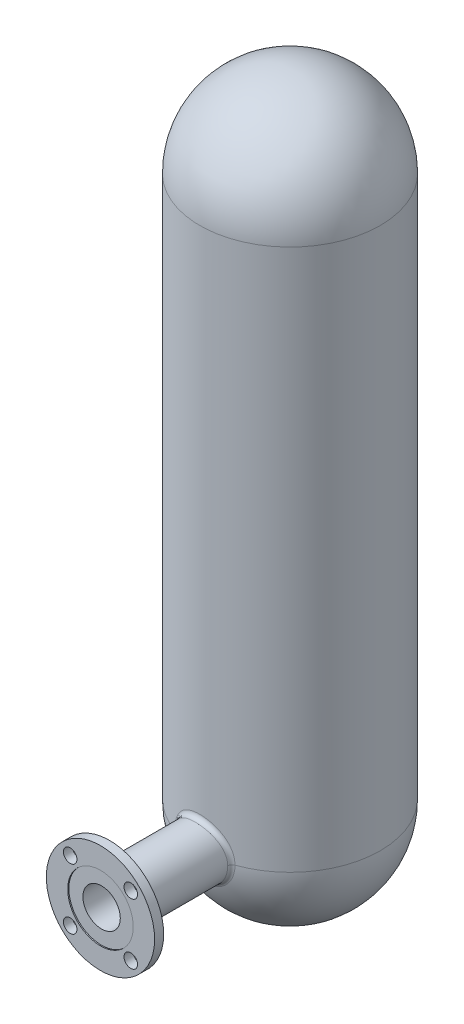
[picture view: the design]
ISO-10303-21;
HEADER;
FILE_DESCRIPTION(('STEP AP214'),'2;1');
FILE_NAME('part.step','',(''),(''),'','','');
FILE_SCHEMA(('AUTOMOTIVE_DESIGN { 1 0 10303 214 1 1 1 1 }'));
ENDSEC;
DATA;
#1=APPLICATION_CONTEXT('core data for automotive mechanical design processes');
#2=APPLICATION_PROTOCOL_DEFINITION('international standard','automotive_design',2000,#1);
#3=PRODUCT_CONTEXT('',#1,'mechanical');
#4=PRODUCT('Part','Part','',(#3));
#5=PRODUCT_RELATED_PRODUCT_CATEGORY('part','',(#4));
#6=PRODUCT_DEFINITION_FORMATION('','',#4);
#7=PRODUCT_DEFINITION_CONTEXT('part definition',#1,'design');
#8=PRODUCT_DEFINITION('design','',#6,#7);
#9=PRODUCT_DEFINITION_SHAPE('','',#8);
#10=(LENGTH_UNIT() NAMED_UNIT(*) SI_UNIT(.MILLI.,.METRE.));
#11=(NAMED_UNIT(*) PLANE_ANGLE_UNIT() SI_UNIT($,.RADIAN.));
#12=(NAMED_UNIT(*) SI_UNIT($,.STERADIAN.) SOLID_ANGLE_UNIT());
#13=UNCERTAINTY_MEASURE_WITH_UNIT(LENGTH_MEASURE(1.E-05),#10,'distance_accuracy_value','');
#14=(GEOMETRIC_REPRESENTATION_CONTEXT(3) GLOBAL_UNCERTAINTY_ASSIGNED_CONTEXT((#13)) GLOBAL_UNIT_ASSIGNED_CONTEXT((#10,
#11,#12)) REPRESENTATION_CONTEXT('',''));
#15=CARTESIAN_POINT('',(0.,0.,0.));
#16=DIRECTION('',(0.,0.,1.));
#17=DIRECTION('',(1.,0.,0.));
#18=AXIS2_PLACEMENT_3D('',#15,#16,#17);
#19=CARTESIAN_POINT('',(0.,0.,0.));
#20=DIRECTION('',(0.,0.,1.));
#21=DIRECTION('',(1.,0.,0.));
#22=AXIS2_PLACEMENT_3D('',#19,#20,#21);
#23=PLANE('',#22);
#24=CARTESIAN_POINT('',(0.,0.,0.));
#25=DIRECTION('',(0.,0.,1.));
#26=DIRECTION('',(1.,0.,0.));
#27=AXIS2_PLACEMENT_3D('',#24,#25,#26);
#28=CIRCLE('',#27,44.45);
#29=CARTESIAN_POINT('',(44.45,0.,0.));
#30=VERTEX_POINT('',#29);
#31=EDGE_CURVE('E81',#30,#30,#28,.T.);
#32=ORIENTED_EDGE('',*,*,#31,.T.);
#33=EDGE_LOOP('',(#32));
#34=FACE_BOUND('',#33,.T.);
#35=CARTESIAN_POINT('',(-42.6562165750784,42.6562165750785,0.));
#36=DIRECTION('',(0.,0.,1.));
#37=DIRECTION('',(0.,1.,0.));
#38=AXIS2_PLACEMENT_3D('',#35,#36,#37);
#39=CIRCLE('',#38,9.525);
#40=CARTESIAN_POINT('',(-42.6562165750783,52.1812165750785,0.));
#41=VERTEX_POINT('',#40);
#42=EDGE_CURVE('E136',#41,#41,#39,.T.);
#43=ORIENTED_EDGE('',*,*,#42,.T.);
#44=EDGE_LOOP('',(#43));
#45=FACE_BOUND('',#44,.T.);
#46=CARTESIAN_POINT('',(42.6562165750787,-42.6562165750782,0.));
#47=DIRECTION('',(0.,0.,1.));
#48=DIRECTION('',(0.,-1.,0.));
#49=AXIS2_PLACEMENT_3D('',#46,#47,#48);
#50=CIRCLE('',#49,9.525);
#51=CARTESIAN_POINT('',(42.6562165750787,-52.1812165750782,0.));
#52=VERTEX_POINT('',#51);
#53=EDGE_CURVE('E148',#52,#52,#50,.T.);
#54=ORIENTED_EDGE('',*,*,#53,.T.);
#55=EDGE_LOOP('',(#54));
#56=FACE_BOUND('',#55,.T.);
#57=CARTESIAN_POINT('',(0.,0.,0.));
#58=DIRECTION('',(0.,0.,1.));
#59=DIRECTION('',(1.,0.,0.));
#60=AXIS2_PLACEMENT_3D('',#57,#58,#59);
#61=CIRCLE('',#60,76.2);
#62=CARTESIAN_POINT('',(76.2,0.,0.));
#63=VERTEX_POINT('',#62);
#64=EDGE_CURVE('E155',#63,#63,#61,.T.);
#65=ORIENTED_EDGE('',*,*,#64,.F.);
#66=EDGE_LOOP('',(#65));
#67=FACE_BOUND('',#66,.T.);
#68=CARTESIAN_POINT('',(42.6562165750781,42.6562165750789,0.));
#69=DIRECTION('',(0.,0.,1.));
#70=DIRECTION('',(1.,0.,0.));
#71=AXIS2_PLACEMENT_3D('',#68,#69,#70);
#72=CIRCLE('',#71,9.525);
#73=CARTESIAN_POINT('',(52.1812165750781,42.6562165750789,0.));
#74=VERTEX_POINT('',#73);
#75=EDGE_CURVE('E151',#74,#74,#72,.T.);
#76=ORIENTED_EDGE('',*,*,#75,.T.);
#77=EDGE_LOOP('',(#76));
#78=FACE_BOUND('',#77,.T.);
#79=CARTESIAN_POINT('',(-42.6562165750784,-42.6562165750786,0.));
#80=DIRECTION('',(0.,0.,1.));
#81=DIRECTION('',(-1.,0.,0.));
#82=AXIS2_PLACEMENT_3D('',#79,#80,#81);
#83=CIRCLE('',#82,9.525);
#84=CARTESIAN_POINT('',(-52.1812165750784,-42.6562165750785,0.));
#85=VERTEX_POINT('',#84);
#86=EDGE_CURVE('E142',#85,#85,#83,.T.);
#87=ORIENTED_EDGE('',*,*,#86,.T.);
#88=EDGE_LOOP('',(#87));
#89=FACE_BOUND('',#88,.T.);
#90=ADVANCED_FACE('F34',(#34,#45,#56,#67,#78,#89),#23,.F.);
#91=CARTESIAN_POINT('',(0.,0.,12.7));
#92=DIRECTION('',(0.,0.,1.));
#93=DIRECTION('',(1.,0.,0.));
#94=AXIS2_PLACEMENT_3D('',#91,#92,#93);
#95=PLANE('',#94);
#96=CARTESIAN_POINT('',(0.,0.,12.7000000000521));
#97=DIRECTION('',(0.,0.,1.));
#98=DIRECTION('',(1.,0.,0.));
#99=AXIS2_PLACEMENT_3D('',#96,#97,#98);
#100=CIRCLE('',#99,46.101);
#101=CARTESIAN_POINT('',(46.101,0.,12.7000000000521));
#102=VERTEX_POINT('',#101);
#103=EDGE_CURVE('E346',#102,#102,#100,.T.);
#104=ORIENTED_EDGE('',*,*,#103,.F.);
#105=EDGE_LOOP('',(#104));
#106=FACE_BOUND('',#105,.T.);
#107=CARTESIAN_POINT('',(-42.6562165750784,-42.6562165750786,12.7));
#108=DIRECTION('',(0.,0.,1.));
#109=DIRECTION('',(-1.,0.,0.));
#110=AXIS2_PLACEMENT_3D('',#107,#108,#109);
#111=CIRCLE('',#110,9.525);
#112=CARTESIAN_POINT('',(-52.1812165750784,-42.6562165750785,12.7));
#113=VERTEX_POINT('',#112);
#114=EDGE_CURVE('E139',#113,#113,#111,.T.);
#115=ORIENTED_EDGE('',*,*,#114,.F.);
#116=EDGE_LOOP('',(#115));
#117=FACE_BOUND('',#116,.T.);
#118=CARTESIAN_POINT('',(42.6562165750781,42.6562165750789,12.7));
#119=DIRECTION('',(0.,0.,1.));
#120=DIRECTION('',(1.,0.,0.));
#121=AXIS2_PLACEMENT_3D('',#118,#119,#120);
#122=CIRCLE('',#121,9.525);
#123=CARTESIAN_POINT('',(52.1812165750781,42.6562165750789,12.7));
#124=VERTEX_POINT('',#123);
#125=EDGE_CURVE('E152',#124,#124,#122,.T.);
#126=ORIENTED_EDGE('',*,*,#125,.F.);
#127=EDGE_LOOP('',(#126));
#128=FACE_BOUND('',#127,.T.);
#129=CARTESIAN_POINT('',(0.,0.,12.7));
#130=DIRECTION('',(0.,0.,1.));
#131=DIRECTION('',(1.,0.,0.));
#132=AXIS2_PLACEMENT_3D('',#129,#130,#131);
#133=CIRCLE('',#132,76.2);
#134=CARTESIAN_POINT('',(76.2,0.,12.7));
#135=VERTEX_POINT('',#134);
#136=EDGE_CURVE('E75',#135,#135,#133,.T.);
#137=ORIENTED_EDGE('',*,*,#136,.T.);
#138=EDGE_LOOP('',(#137));
#139=FACE_BOUND('',#138,.T.);
#140=CARTESIAN_POINT('',(42.6562165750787,-42.6562165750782,12.7));
#141=DIRECTION('',(0.,0.,1.));
#142=DIRECTION('',(0.,-1.,0.));
#143=AXIS2_PLACEMENT_3D('',#140,#141,#142);
#144=CIRCLE('',#143,9.525);
#145=CARTESIAN_POINT('',(42.6562165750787,-52.1812165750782,12.7));
#146=VERTEX_POINT('',#145);
#147=EDGE_CURVE('E145',#146,#146,#144,.T.);
#148=ORIENTED_EDGE('',*,*,#147,.F.);
#149=EDGE_LOOP('',(#148));
#150=FACE_BOUND('',#149,.T.);
#151=CARTESIAN_POINT('',(-42.6562165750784,42.6562165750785,12.7));
#152=DIRECTION('',(0.,0.,1.));
#153=DIRECTION('',(0.,1.,0.));
#154=AXIS2_PLACEMENT_3D('',#151,#152,#153);
#155=CIRCLE('',#154,9.525);
#156=CARTESIAN_POINT('',(-42.6562165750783,52.1812165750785,12.7));
#157=VERTEX_POINT('',#156);
#158=EDGE_CURVE('E129',#157,#157,#155,.T.);
#159=ORIENTED_EDGE('',*,*,#158,.F.);
#160=EDGE_LOOP('',(#159));
#161=FACE_BOUND('',#160,.T.);
#162=ADVANCED_FACE('F166',(#106,#117,#128,#139,#150,#161),#95,.T.);
#163=CARTESIAN_POINT('',(0.,0.,12.7));
#164=DIRECTION('',(0.,0.,-1.));
#165=DIRECTION('',(-1.,0.,0.));
#166=AXIS2_PLACEMENT_3D('',#163,#164,#165);
#167=CYLINDRICAL_SURFACE('',#166,76.2);
#168=ORIENTED_EDGE('',*,*,#136,.F.);
#169=EDGE_LOOP('',(#168));
#170=FACE_BOUND('',#169,.T.);
#171=ORIENTED_EDGE('',*,*,#64,.T.);
#172=EDGE_LOOP('',(#171));
#173=FACE_BOUND('',#172,.T.);
#174=ADVANCED_FACE('F162',(#170,#173),#167,.T.);
#175=CARTESIAN_POINT('',(42.6562165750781,42.6562165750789,12.7));
#176=DIRECTION('',(0.,0.,-1.));
#177=DIRECTION('',(-1.,0.,0.));
#178=AXIS2_PLACEMENT_3D('',#175,#176,#177);
#179=CYLINDRICAL_SURFACE('',#178,9.525);
#180=ORIENTED_EDGE('',*,*,#125,.T.);
#181=EDGE_LOOP('',(#180));
#182=FACE_BOUND('',#181,.T.);
#183=ORIENTED_EDGE('',*,*,#75,.F.);
#184=EDGE_LOOP('',(#183));
#185=FACE_BOUND('',#184,.T.);
#186=ADVANCED_FACE('F184',(#182,#185),#179,.F.);
#187=CARTESIAN_POINT('',(42.6562165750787,-42.6562165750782,12.7));
#188=DIRECTION('',(0.,0.,-1.));
#189=DIRECTION('',(0.,1.,0.));
#190=AXIS2_PLACEMENT_3D('',#187,#188,#189);
#191=CYLINDRICAL_SURFACE('',#190,9.525);
#192=ORIENTED_EDGE('',*,*,#147,.T.);
#193=EDGE_LOOP('',(#192));
#194=FACE_BOUND('',#193,.T.);
#195=ORIENTED_EDGE('',*,*,#53,.F.);
#196=EDGE_LOOP('',(#195));
#197=FACE_BOUND('',#196,.T.);
#198=ADVANCED_FACE('F176',(#194,#197),#191,.F.);
#199=CARTESIAN_POINT('',(-42.6562165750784,-42.6562165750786,12.7));
#200=DIRECTION('',(0.,0.,-1.));
#201=DIRECTION('',(1.,0.,0.));
#202=AXIS2_PLACEMENT_3D('',#199,#200,#201);
#203=CYLINDRICAL_SURFACE('',#202,9.525);
#204=ORIENTED_EDGE('',*,*,#114,.T.);
#205=EDGE_LOOP('',(#204));
#206=FACE_BOUND('',#205,.T.);
#207=ORIENTED_EDGE('',*,*,#86,.F.);
#208=EDGE_LOOP('',(#207));
#209=FACE_BOUND('',#208,.T.);
#210=ADVANCED_FACE('F173',(#206,#209),#203,.F.);
#211=CARTESIAN_POINT('',(-42.6562165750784,42.6562165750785,12.7));
#212=DIRECTION('',(0.,0.,-1.));
#213=DIRECTION('',(0.,-1.,0.));
#214=AXIS2_PLACEMENT_3D('',#211,#212,#213);
#215=CYLINDRICAL_SURFACE('',#214,9.525);
#216=ORIENTED_EDGE('',*,*,#158,.T.);
#217=EDGE_LOOP('',(#216));
#218=FACE_BOUND('',#217,.T.);
#219=ORIENTED_EDGE('',*,*,#42,.F.);
#220=EDGE_LOOP('',(#219));
#221=FACE_BOUND('',#220,.T.);
#222=ADVANCED_FACE('F175',(#218,#221),#215,.F.);
#223=CARTESIAN_POINT('',(0.,0.,-254.));
#224=DIRECTION('',(0.,0.,1.));
#225=DIRECTION('',(1.,0.,0.));
#226=AXIS2_PLACEMENT_3D('',#223,#224,#225);
#227=CYLINDRICAL_SURFACE('',#226,38.1);
#228=CARTESIAN_POINT('',(0.,0.,-6.34999999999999));
#229=DIRECTION('',(0.,0.,1.));
#230=DIRECTION('',(1.,0.,0.));
#231=AXIS2_PLACEMENT_3D('',#228,#229,#230);
#232=CIRCLE('',#231,38.1);
#233=CARTESIAN_POINT('',(38.1,0.,-6.34999999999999));
#234=VERTEX_POINT('',#233);
#235=EDGE_CURVE('E78',#234,#234,#232,.F.);
#236=ORIENTED_EDGE('',*,*,#235,.T.);
#237=EDGE_LOOP('',(#236));
#238=FACE_BOUND('',#237,.T.);
#239=CARTESIAN_POINT('',(36.0912363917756,-12.2078931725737,-127.472255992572));
#240=CARTESIAN_POINT('',(35.9327782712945,-12.6763564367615,-132.110143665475));
#241=CARTESIAN_POINT('',(40.1013737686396,-14.2425420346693,-133.497386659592));
#242=CARTESIAN_POINT('',(36.2566669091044,-11.7188156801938,-127.536488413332));
#243=CARTESIAN_POINT('',(36.1103315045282,-12.1723584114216,-132.162177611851));
#244=CARTESIAN_POINT('',(40.2851854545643,-13.6719516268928,-133.558560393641));
#245=CARTESIAN_POINT('',(36.4122340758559,-11.2261412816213,-127.597372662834));
#246=CARTESIAN_POINT('',(36.2776912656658,-11.6634311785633,-132.211645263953));
#247=CARTESIAN_POINT('',(40.4580378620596,-13.0971648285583,-133.616545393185));
#248=CARTESIAN_POINT('',(36.7033555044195,-10.2343004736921,-127.712025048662));
#249=CARTESIAN_POINT('',(36.5910783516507,-10.637885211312,-132.304902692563));
#250=CARTESIAN_POINT('',(40.7815061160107,-11.9400172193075,-133.725738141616));
#251=CARTESIAN_POINT('',(36.838909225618,-9.73513388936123,-127.765792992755));
#252=CARTESIAN_POINT('',(36.7371824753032,-10.1211577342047,-132.348714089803));
#253=CARTESIAN_POINT('',(40.9321213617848,-11.3576562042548,-133.776945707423));
#254=CARTESIAN_POINT('',(37.2150749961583,-8.22912180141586,-127.915774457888));
#255=CARTESIAN_POINT('',(37.142471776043,-8.56214817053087,-132.470927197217));
#256=CARTESIAN_POINT('',(41.3500833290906,-9.60064210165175,-133.919785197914));
#257=CARTESIAN_POINT('',(37.4252357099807,-7.21363378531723,-128.000682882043));
#258=CARTESIAN_POINT('',(37.3697428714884,-7.50766486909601,-132.540437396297));
#259=CARTESIAN_POINT('',(41.583595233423,-8.41590608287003,-134.000650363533));
#260=CARTESIAN_POINT('',(37.7619395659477,-5.1689618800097,-128.137495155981));
#261=CARTESIAN_POINT('',(37.7337564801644,-5.38291751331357,-132.652459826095));
#262=CARTESIAN_POINT('',(41.9577106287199,-6.03045552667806,-134.130947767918));
#263=CARTESIAN_POINT('',(37.8886076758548,-4.13980082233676,-128.189448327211));
#264=CARTESIAN_POINT('',(37.8710238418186,-4.31159426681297,-132.695130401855));
#265=CARTESIAN_POINT('',(42.0984529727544,-4.82976762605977,-134.180426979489));
#266=CARTESIAN_POINT('',(38.0576344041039,-2.07375805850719,-128.258906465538));
#267=CARTESIAN_POINT('',(38.0540409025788,-2.16076039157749,-132.752139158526));
#268=CARTESIAN_POINT('',(42.286260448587,-2.41938440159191,-134.246577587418));
#269=CARTESIAN_POINT('',(38.0999992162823,-1.03687692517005,-128.276413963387));
#270=CARTESIAN_POINT('',(38.0999991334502,-1.08007747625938,-132.766542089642));
#271=CARTESIAN_POINT('',(42.3333324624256,-1.20968974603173,-134.263251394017));
#272=CARTESIAN_POINT('',(38.1000007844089,1.03779139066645,-128.276414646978));
#273=CARTESIAN_POINT('',(38.1000008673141,1.08103003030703,-132.766542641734));
#274=CARTESIAN_POINT('',(42.3333342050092,1.21075662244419,-134.263252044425));
#275=CARTESIAN_POINT('',(38.0575627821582,2.07557856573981,-128.258876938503));
#276=CARTESIAN_POINT('',(38.0539632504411,2.16265900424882,-132.752114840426));
#277=CARTESIAN_POINT('',(42.2861808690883,2.42150832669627,-134.246549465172));
#278=CARTESIAN_POINT('',(37.8882350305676,4.14340805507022,-128.189295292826));
#279=CARTESIAN_POINT('',(37.8706200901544,4.31534930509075,-132.695004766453));
#280=CARTESIAN_POINT('',(42.0980389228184,4.83397606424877,-134.180281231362));
#281=CARTESIAN_POINT('',(37.7613425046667,5.17345011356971,-128.137250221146));
#282=CARTESIAN_POINT('',(37.7331089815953,5.38758654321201,-132.652258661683));
#283=CARTESIAN_POINT('',(41.9570472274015,6.03569179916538,-134.130714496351));
#284=CARTESIAN_POINT('',(37.4243865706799,7.21792363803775,-128.000340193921));
#285=CARTESIAN_POINT('',(37.3688262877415,7.51211915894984,-132.540157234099));
#286=CARTESIAN_POINT('',(41.5826517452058,8.42091091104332,-134.000323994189));
#287=CARTESIAN_POINT('',(37.2143439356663,8.23235893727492,-127.915483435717));
#288=CARTESIAN_POINT('',(37.1416862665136,8.56550890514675,-132.470690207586));
#289=CARTESIAN_POINT('',(41.3492710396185,9.60441876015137,-133.919508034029));
#290=CARTESIAN_POINT('',(36.7130537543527,10.2386960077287,-127.715612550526));
#291=CARTESIAN_POINT('',(36.6011422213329,10.6441169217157,-132.307691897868));
#292=CARTESIAN_POINT('',(40.792281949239,11.9451453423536,-133.729154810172));
#293=CARTESIAN_POINT('',(36.4218065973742,11.2305978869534,-127.600598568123));
#294=CARTESIAN_POINT('',(36.287186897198,11.6702872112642,-132.214000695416));
#295=CARTESIAN_POINT('',(40.4686739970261,13.1023642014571,-133.619617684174));
#296=CARTESIAN_POINT('',(35.7613126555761,13.1832772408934,-127.344164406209));
#297=CARTESIAN_POINT('',(35.5775691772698,13.6846979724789,-132.006052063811));
#298=CARTESIAN_POINT('',(39.7347918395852,15.3804901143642,-133.375394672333));
#299=CARTESIAN_POINT('',(35.3922195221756,14.1441117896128,-127.202796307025));
#300=CARTESIAN_POINT('',(35.1813925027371,14.6737879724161,-131.891651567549));
#301=CARTESIAN_POINT('',(39.3246883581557,16.5014637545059,-133.240758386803));
#302=CARTESIAN_POINT('',(34.5786856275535,16.0305867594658,-126.897639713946));
#303=CARTESIAN_POINT('',(34.3114651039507,16.6092272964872,-131.645987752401));
#304=CARTESIAN_POINT('',(38.4207618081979,18.7023512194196,-132.950133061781));
#305=CARTESIAN_POINT('',(34.1342447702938,16.9562271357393,-126.733851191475));
#306=CARTESIAN_POINT('',(33.8369634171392,17.5561426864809,-131.514538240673));
#307=CARTESIAN_POINT('',(37.9269386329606,19.7822649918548,-132.794143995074));
#308=CARTESIAN_POINT('',(33.1731253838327,18.767125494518,-126.388388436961));
#309=CARTESIAN_POINT('',(32.8151827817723,19.4015005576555,-131.2389049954));
#310=CARTESIAN_POINT('',(36.8590282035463,21.8949797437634,-132.465131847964));
#311=CARTESIAN_POINT('',(32.656416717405,19.6523664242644,-126.206706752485));
#312=CARTESIAN_POINT('',(32.2670919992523,20.3002661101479,-131.094546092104));
#313=CARTESIAN_POINT('',(36.2849074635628,22.9277608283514,-132.292101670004));
#314=CARTESIAN_POINT('',(31.5544193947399,21.376995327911,-125.830432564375));
#315=CARTESIAN_POINT('',(31.1036390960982,22.0436031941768,-130.797505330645));
#316=CARTESIAN_POINT('',(35.06046599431,24.9398278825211,-131.933745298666));
#317=CARTESIAN_POINT('',(30.9691265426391,22.216380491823,-125.635839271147));
#318=CARTESIAN_POINT('',(30.4875092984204,22.8882903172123,-130.644686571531));
#319=CARTESIAN_POINT('',(34.4101406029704,25.9191105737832,-131.748418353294));
#320=CARTESIAN_POINT('',(29.7117893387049,23.8733988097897,-125.231814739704));
#321=CARTESIAN_POINT('',(29.1705268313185,24.5479246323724,-130.329599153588));
#322=CARTESIAN_POINT('',(33.0130992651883,27.852298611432,-131.363633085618));
#323=CARTESIAN_POINT('',(29.0374061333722,24.6892076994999,-125.022102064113));
#324=CARTESIAN_POINT('',(28.4668590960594,25.3604303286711,-130.167131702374));
#325=CARTESIAN_POINT('',(32.2637845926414,28.8040756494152,-131.163906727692));
#326=CARTESIAN_POINT('',(27.623414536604,26.2616647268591,-124.60004915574));
#327=CARTESIAN_POINT('',(26.9999251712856,26.9180050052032,-129.842737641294));
#328=CARTESIAN_POINT('',(30.6926828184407,30.6386088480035,-130.76195157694));
#329=CARTESIAN_POINT('',(26.8838047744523,27.018311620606,-124.387708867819));
#330=CARTESIAN_POINT('',(26.2360241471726,27.6627219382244,-129.68077834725));
#331=CARTESIAN_POINT('',(29.8708941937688,31.5213635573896,-130.559722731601));
#332=CARTESIAN_POINT('',(25.3438370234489,28.4678436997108,-123.966087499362));
#333=CARTESIAN_POINT('',(24.655136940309,29.0811491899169,-129.361862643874));
#334=CARTESIAN_POINT('',(28.1598189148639,33.2124843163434,-130.158178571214));
#335=CARTESIAN_POINT('',(24.5434749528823,29.1607245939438,-123.756806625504));
#336=CARTESIAN_POINT('',(23.8377053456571,29.7542961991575,-129.204943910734));
#337=CARTESIAN_POINT('',(27.2705277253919,34.0208453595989,-129.958863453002));
#338=CARTESIAN_POINT('',(22.8868938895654,30.4781898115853,-123.346891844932));
#339=CARTESIAN_POINT('',(22.1564501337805,31.0265686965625,-128.900215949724));
#340=CARTESIAN_POINT('',(25.429882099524,35.5578881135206,-129.568468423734));
#341=CARTESIAN_POINT('',(22.0306765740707,31.1027761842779,-123.146257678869));
#342=CARTESIAN_POINT('',(21.2924252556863,31.6249709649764,-128.752510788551));
#343=CARTESIAN_POINT('',(24.4785295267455,36.2865722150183,-129.377388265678));
#344=CARTESIAN_POINT('',(20.2444054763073,32.2948436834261,-122.753882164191));
#345=CARTESIAN_POINT('',(19.5011564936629,32.7603168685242,-128.466084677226));
#346=CARTESIAN_POINT('',(22.4937838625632,37.6773176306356,-129.003697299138));
#347=CARTESIAN_POINT('',(19.313004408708,32.8603983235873,-122.562511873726));
#348=CARTESIAN_POINT('',(18.5731161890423,33.2942210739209,-128.327902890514));
#349=CARTESIAN_POINT('',(21.4588937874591,38.3371313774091,-128.821439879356));
#350=CARTESIAN_POINT('',(17.4029087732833,33.9107160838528,-122.199890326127));
#351=CARTESIAN_POINT('',(16.6820238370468,34.2799368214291,-128.06825649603));
#352=CARTESIAN_POINT('',(19.3365653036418,39.5625020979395,-128.476086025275));
#353=CARTESIAN_POINT('',(16.4242131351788,34.3954773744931,-122.0286395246));
#354=CARTESIAN_POINT('',(15.7193877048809,34.7307738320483,-127.94701153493));
#355=CARTESIAN_POINT('',(18.2491257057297,40.1280569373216,-128.312990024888));
#356=CARTESIAN_POINT('',(14.4264482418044,35.2800326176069,-121.711196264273));
#357=CARTESIAN_POINT('',(13.7659727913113,35.5491026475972,-127.723954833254));
#358=CARTESIAN_POINT('',(16.0293869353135,41.1600380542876,-128.010663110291));
#359=CARTESIAN_POINT('',(13.40738615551,35.6798415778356,-121.56499938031));
#360=CARTESIAN_POINT('',(12.7759558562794,35.9156498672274,-127.622378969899));
#361=CARTESIAN_POINT('',(14.8970957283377,41.6264818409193,-127.871427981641));
#362=CARTESIAN_POINT('',(11.3361359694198,36.3909438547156,-121.301900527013));
#363=CARTESIAN_POINT('',(10.7739336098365,36.5648280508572,-127.440709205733));
#364=CARTESIAN_POINT('',(12.5957066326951,42.4561011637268,-127.620857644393));
#365=CARTESIAN_POINT('',(10.2839492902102,36.7022409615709,-121.184997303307));
#366=CARTESIAN_POINT('',(9.7630109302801,36.8465915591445,-127.3608467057));
#367=CARTESIAN_POINT('',(11.4266103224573,42.8192811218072,-127.509521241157));
#368=CARTESIAN_POINT('',(8.19154249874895,37.2240578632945,-120.987455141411));
#369=CARTESIAN_POINT('',(7.76061984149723,37.3175291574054,-127.226485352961));
#370=CARTESIAN_POINT('',(9.10171388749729,43.4280675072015,-127.321385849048));
#371=CARTESIAN_POINT('',(7.15218026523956,37.4377078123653,-120.905695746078));
#372=CARTESIAN_POINT('',(6.77079754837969,37.5089671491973,-127.171372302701));
#373=CARTESIAN_POINT('',(7.94686696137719,43.677325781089,-127.243519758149));
#374=CARTESIAN_POINT('',(5.05776764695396,37.777697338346,-120.775000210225));
#375=CARTESIAN_POINT('',(4.78094839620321,37.8132586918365,-127.083450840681));
#376=CARTESIAN_POINT('',(5.61974182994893,44.073980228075,-127.119047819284));
#377=CARTESIAN_POINT('',(4.00271759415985,37.9040387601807,-120.72606337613));
#378=CARTESIAN_POINT('',(3.7823341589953,37.9256640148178,-127.050770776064));
#379=CARTESIAN_POINT('',(4.44746399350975,44.2213785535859,-127.07244131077));
#380=CARTESIAN_POINT('',(1.88523628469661,38.0681403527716,-120.662415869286));
#381=CARTESIAN_POINT('',(1.77967959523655,38.0717694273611,-127.008247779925));
#382=CARTESIAN_POINT('',(2.09470698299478,44.4128304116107,-127.011824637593));
#383=CARTESIAN_POINT('',(0.822806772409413,38.1059207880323,-120.647697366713));
#384=CARTESIAN_POINT('',(0.777168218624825,38.105262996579,-126.998464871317));
#385=CARTESIAN_POINT('',(0.914229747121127,44.4569075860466,-126.997807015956));
#386=CARTESIAN_POINT('',(-1.30141903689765,38.0925761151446,-120.652887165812));
#387=CARTESIAN_POINT('',(-1.22907519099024,38.0934016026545,-127.001924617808));
#388=CARTESIAN_POINT('',(-1.44602115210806,44.4413388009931,-127.002749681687));
#389=CARTESIAN_POINT('',(-2.36321534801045,38.0414530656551,-120.67279466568));
#390=CARTESIAN_POINT('',(-2.23124385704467,38.0480669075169,-127.015161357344));
#391=CARTESIAN_POINT('',(-2.62579483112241,44.3816952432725,-127.021709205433));
#392=CARTESIAN_POINT('',(-4.43637562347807,37.8545764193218,-120.745206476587));
#393=CARTESIAN_POINT('',(-4.19299785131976,37.8815817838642,-127.06357823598));
#394=CARTESIAN_POINT('',(-4.92930624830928,44.1636724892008,-127.090672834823));
#395=CARTESIAN_POINT('',(-5.44808226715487,37.72222609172,-120.796399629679));
#396=CARTESIAN_POINT('',(-5.15127731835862,37.7637187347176,-127.097806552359));
#397=CARTESIAN_POINT('',(-6.05342474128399,44.0092637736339,-127.139428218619));
#398=CARTESIAN_POINT('',(-7.45619165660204,37.3771728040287,-120.928859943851));
#399=CARTESIAN_POINT('',(-7.06043277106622,37.4546549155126,-127.18700660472));
#400=CARTESIAN_POINT('',(-8.28465739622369,43.6067016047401,-127.26558089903));
#401=CARTESIAN_POINT('',(-8.45259487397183,37.1644723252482,-121.010126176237));
#402=CARTESIAN_POINT('',(-8.01007322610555,37.263875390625,-127.241858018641));
#403=CARTESIAN_POINT('',(-9.39177208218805,43.3585510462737,-127.342977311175));
#404=CARTESIAN_POINT('',(-10.4233648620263,36.6605785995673,-121.200627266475));
#405=CARTESIAN_POINT('',(-9.89735195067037,36.8087579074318,-127.371560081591));
#406=CARTESIAN_POINT('',(-11.5815165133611,42.7706750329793,-127.524406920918));
#407=CARTESIAN_POINT('',(-11.3977306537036,36.3693818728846,-121.309863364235));
#408=CARTESIAN_POINT('',(-10.8339183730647,36.5449936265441,-127.446251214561));
#409=CARTESIAN_POINT('',(-12.6641451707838,42.4309455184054,-127.628441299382));
#410=CARTESIAN_POINT('',(-13.3180269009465,35.7109297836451,-121.553511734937));
#411=CARTESIAN_POINT('',(-12.6899398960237,35.9439176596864,-127.614476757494));
#412=CARTESIAN_POINT('',(-14.7978076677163,41.662751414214,-127.860487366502));
#413=CARTESIAN_POINT('',(-14.2639567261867,35.3436727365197,-121.687924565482));
#414=CARTESIAN_POINT('',(-13.6085321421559,35.6072977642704,-127.707826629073));
#415=CARTESIAN_POINT('',(-15.8488408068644,41.2342848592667,-127.988499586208));
#416=CARTESIAN_POINT('',(-16.1336707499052,34.5306746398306,-121.980461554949));
#417=CARTESIAN_POINT('',(-15.4349546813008,34.8560109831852,-127.913082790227));
#418=CARTESIAN_POINT('',(-17.9263008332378,40.2857870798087,-128.267106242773));
#419=CARTESIAN_POINT('',(-17.0570008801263,34.083966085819,-122.13887396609));
#420=CARTESIAN_POINT('',(-16.341914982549,34.4411328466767,-128.025027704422));
#421=CARTESIAN_POINT('',(-18.9522232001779,39.7646271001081,-128.417975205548));
#422=CARTESIAN_POINT('',(-18.8627678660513,33.118788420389,-122.474065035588));
#423=CARTESIAN_POINT('',(-18.126582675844,33.537150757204,-128.2643966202));
#424=CARTESIAN_POINT('',(-20.9586309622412,38.638586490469,-128.737204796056));
#425=CARTESIAN_POINT('',(-19.7452045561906,32.6003190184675,-122.650843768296));
#426=CARTESIAN_POINT('',(-19.0039061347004,33.0488539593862,-128.391635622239));
#427=CARTESIAN_POINT('',(-21.9391161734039,38.0337055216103,-128.905565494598));
#428=CARTESIAN_POINT('',(-21.4641863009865,31.4951262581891,-123.018387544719));
#429=CARTESIAN_POINT('',(-20.7231785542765,31.9994148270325,-128.658885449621));
#430=CARTESIAN_POINT('',(-23.8490958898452,36.7443139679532,-129.255607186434));
#431=CARTESIAN_POINT('',(-22.3007235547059,30.908391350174,-123.209154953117));
#432=CARTESIAN_POINT('',(-21.5650012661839,31.4390284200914,-128.79874531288));
#433=CARTESIAN_POINT('',(-24.7785817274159,36.0597899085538,-129.437290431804));
#434=CARTESIAN_POINT('',(-23.9230317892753,29.6705195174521,-123.599934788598));
#435=CARTESIAN_POINT('',(-23.2067597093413,30.2475683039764,-129.087989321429));
#436=CARTESIAN_POINT('',(-26.5811464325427,34.6156061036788,-129.809461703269));
#437=CARTESIAN_POINT('',(-24.708800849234,29.0193801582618,-123.799947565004));
#438=CARTESIAN_POINT('',(-24.0068184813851,29.6171708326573,-129.237267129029));
#439=CARTESIAN_POINT('',(-27.4542231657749,33.8559435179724,-129.99995006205));
#440=CARTESIAN_POINT('',(-26.2608053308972,27.6246091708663,-124.21378311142));
#441=CARTESIAN_POINT('',(-25.5948668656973,28.2574325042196,-129.548775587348));
#442=CARTESIAN_POINT('',(-29.1786725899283,32.2287106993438,-130.394079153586));
#443=CARTESIAN_POINT('',(-27.0243898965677,26.8780697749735,-124.427813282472));
#444=CARTESIAN_POINT('',(-26.3812073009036,27.52518935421,-129.711287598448));
#445=CARTESIAN_POINT('',(-30.0270998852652,31.3577480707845,-130.597917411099));
#446=CARTESIAN_POINT('',(-28.4863430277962,25.3234486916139,-124.854762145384));
#447=CARTESIAN_POINT('',(-27.8937734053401,25.9901289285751,-130.038087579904));
#448=CARTESIAN_POINT('',(-31.6514922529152,29.5440234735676,-131.004535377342));
#449=CARTESIAN_POINT('',(-29.1847091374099,24.5153646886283,-125.067680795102));
#450=CARTESIAN_POINT('',(-28.6206015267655,25.1877289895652,-130.202390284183));
#451=CARTESIAN_POINT('',(-32.427454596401,28.6012588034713,-131.207315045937));
#452=CARTESIAN_POINT('',(-30.5121453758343,22.8420588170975,-125.486638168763));
#453=CARTESIAN_POINT('',(-30.0075871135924,23.5165200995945,-130.527920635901));
#454=CARTESIAN_POINT('',(-33.9023837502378,26.6490686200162,-131.606322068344));
#455=CARTESIAN_POINT('',(-31.1411810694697,21.9768088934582,-125.692673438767));
#456=CARTESIAN_POINT('',(-30.6684754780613,22.6478591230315,-130.689231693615));
#457=CARTESIAN_POINT('',(-34.6013122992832,25.6396103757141,-131.802546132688));
#458=CARTESIAN_POINT('',(-32.0289964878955,20.6407247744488,-125.992004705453));
#459=CARTESIAN_POINT('',(-31.6058498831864,21.2975934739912,-130.92532855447));
#460=CARTESIAN_POINT('',(-35.5877738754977,24.0808455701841,-132.087623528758));
#461=CARTESIAN_POINT('',(-32.3156517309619,20.1889834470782,-126.090163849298));
#462=CARTESIAN_POINT('',(-31.9086646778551,20.8407809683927,-131.00287194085));
#463=CARTESIAN_POINT('',(-35.9062797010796,23.5538140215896,-132.181108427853));
#464=CARTESIAN_POINT('',(-32.870024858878,19.2732461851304,-126.282579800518));
#465=CARTESIAN_POINT('',(-32.4952414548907,19.9127478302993,-131.155282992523));
#466=CARTESIAN_POINT('',(-36.5222498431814,22.4854538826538,-132.364361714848));
#467=CARTESIAN_POINT('',(-33.1377372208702,18.8092467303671,-126.376835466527));
#468=CARTESIAN_POINT('',(-32.77910875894,19.4414958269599,-131.230171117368));
#469=CARTESIAN_POINT('',(-36.819708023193,21.9441211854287,-132.454129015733));
#470=CARTESIAN_POINT('',(-33.9191888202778,17.3862307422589,-126.65536178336));
#471=CARTESIAN_POINT('',(-33.6075871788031,17.9956636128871,-131.451651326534));
#472=CARTESIAN_POINT('',(-37.6879875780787,20.2839358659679,-132.719392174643));
#473=CARTESIAN_POINT('',(-34.4025483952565,16.4092586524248,-126.832430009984));
#474=CARTESIAN_POINT('',(-34.1232649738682,16.9972296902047,-131.593585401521));
#475=CARTESIAN_POINT('',(-38.2250537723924,19.1441350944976,-132.888028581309));
#476=CARTESIAN_POINT('',(-35.2846913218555,14.4148977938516,-127.161840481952));
#477=CARTESIAN_POINT('',(-35.0659749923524,14.9525653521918,-131.858522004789));
#478=CARTESIAN_POINT('',(-39.2052125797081,16.8173807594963,-133.201752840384));
#479=CARTESIAN_POINT('',(-35.6834784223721,13.3975108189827,-127.314183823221));
#480=CARTESIAN_POINT('',(-35.4939175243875,13.9056890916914,-131.98174726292));
#481=CARTESIAN_POINT('',(-39.6483093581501,15.6304292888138,-133.346841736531));
#482=CARTESIAN_POINT('',(-36.2152196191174,11.8476108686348,-127.520298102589));
#483=CARTESIAN_POINT('',(-36.065733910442,12.3054075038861,-132.149023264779));
#484=CARTESIAN_POINT('',(-40.239132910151,13.8222126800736,-133.54314105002));
#485=CARTESIAN_POINT('',(-36.3813070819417,11.3273532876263,-127.585234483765));
#486=CARTESIAN_POINT('',(-36.2443941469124,11.7680790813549,-132.201773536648));
#487=CARTESIAN_POINT('',(-40.4236745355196,13.2152455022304,-133.604985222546));
#488=CARTESIAN_POINT('',(-36.6910920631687,10.2796937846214,-127.70715891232));
#489=CARTESIAN_POINT('',(-36.5778449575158,10.6849344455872,-132.300932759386));
#490=CARTESIAN_POINT('',(-40.7678800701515,11.9929760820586,-133.721103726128));
#491=CARTESIAN_POINT('',(-36.8347954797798,9.75229378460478,-127.764149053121));
#492=CARTESIAN_POINT('',(-36.7327335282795,10.1389933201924,-132.347369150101));
#493=CARTESIAN_POINT('',(-40.9275505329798,11.3776760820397,-133.775380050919));
#494=CARTESIAN_POINT('',(-37.2317268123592,8.16105390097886,-127.922421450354));
#495=CARTESIAN_POINT('',(-37.1603792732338,8.49180321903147,-132.476334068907));
#496=CARTESIAN_POINT('',(-41.3685853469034,9.52122955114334,-133.926115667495));
#497=CARTESIAN_POINT('',(-37.4509821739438,7.08757292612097,-128.011086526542));
#498=CARTESIAN_POINT('',(-37.3975457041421,7.3769102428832,-132.548942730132));
#499=CARTESIAN_POINT('',(-41.6122024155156,8.26883508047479,-134.01055859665));
#500=CARTESIAN_POINT('',(-37.7820230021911,5.01379669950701,-128.145719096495));
#501=CARTESIAN_POINT('',(-37.7555150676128,5.22141669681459,-132.659211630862));
#502=CARTESIAN_POINT('',(-41.9800255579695,5.84942948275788,-134.138780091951));
#503=CARTESIAN_POINT('',(-37.9012128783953,4.01481465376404,-128.194617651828));
#504=CARTESIAN_POINT('',(-37.8846702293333,4.1814618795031,-132.699371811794));
#505=CARTESIAN_POINT('',(-42.1124587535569,4.68395042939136,-134.18535014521));
#506=CARTESIAN_POINT('',(-38.0204475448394,2.51160892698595,-128.243631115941));
#507=CARTESIAN_POINT('',(-38.0138197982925,2.61610091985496,-132.739615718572));
#508=CARTESIAN_POINT('',(-42.244941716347,2.93021041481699,-134.232029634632));
#509=CARTESIAN_POINT('',(-38.0502673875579,2.00989086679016,-128.255913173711));
#510=CARTESIAN_POINT('',(-38.046124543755,2.09355732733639,-132.74970340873));
#511=CARTESIAN_POINT('',(-42.2780748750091,2.34487267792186,-134.243726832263));
#512=CARTESIAN_POINT('',(-38.0900477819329,1.00547079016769,-128.272307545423));
#513=CARTESIAN_POINT('',(-38.0892151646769,1.04743326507,-132.763167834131));
#514=CARTESIAN_POINT('',(-42.3222753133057,1.17304925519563,-134.259340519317));
#515=CARTESIAN_POINT('',(-38.1000040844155,0.502768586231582,-128.276418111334));
#516=CARTESIAN_POINT('',(-38.1000076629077,0.523716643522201,-132.766546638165));
#517=CARTESIAN_POINT('',(-42.333337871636,0.586563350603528,-134.263255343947));
#518=CARTESIAN_POINT('',(-38.0999915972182,-1.03433520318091,-128.276406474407));
#519=CARTESIAN_POINT('',(-38.0999842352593,-1.07743136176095,-132.766533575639));
#520=CARTESIAN_POINT('',(-42.3333239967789,-1.2067244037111,-134.263244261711));
#521=CARTESIAN_POINT('',(-38.0578268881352,-2.06895136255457,-128.258984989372));
#522=CARTESIAN_POINT('',(-38.0542482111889,-2.15574972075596,-132.752203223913));
#523=CARTESIAN_POINT('',(-42.2864743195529,-2.41377658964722,-134.246652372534));
#524=CARTESIAN_POINT('',(-37.8895404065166,-4.13083911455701,-128.189832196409));
#525=CARTESIAN_POINT('',(-37.87203578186,-4.3022638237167,-132.695446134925));
#526=CARTESIAN_POINT('',(-42.09948933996,-4.81931230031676,-134.180792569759));
#527=CARTESIAN_POINT('',(-37.7633741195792,-5.15810652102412,-128.138082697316));
#528=CARTESIAN_POINT('',(-37.7353110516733,-5.37161987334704,-132.652942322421));
#529=CARTESIAN_POINT('',(-41.9593045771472,-6.01779094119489,-134.131507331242));
#530=CARTESIAN_POINT('',(-37.4272819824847,-7.20333606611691,-128.001509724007));
#531=CARTESIAN_POINT('',(-37.3719528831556,-7.49697742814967,-132.541113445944));
#532=CARTESIAN_POINT('',(-41.5858688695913,-8.40389207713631,-134.00143783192));
#533=CARTESIAN_POINT('',(-37.2168880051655,-8.22121311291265,-127.916501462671));
#534=CARTESIAN_POINT('',(-37.1444266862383,-8.55395427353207,-132.471520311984));
#535=CARTESIAN_POINT('',(-41.3520977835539,-9.591415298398,-133.920477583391));
#536=CARTESIAN_POINT('',(-36.840143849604,-9.73051352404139,-127.766283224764));
#537=CARTESIAN_POINT('',(-36.7385128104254,-10.1163757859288,-132.349113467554));
#538=CARTESIAN_POINT('',(-40.9334931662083,-11.3522657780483,-133.777412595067));
#539=CARTESIAN_POINT('',(-36.7043945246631,-10.2306227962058,-127.712435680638));
#540=CARTESIAN_POINT('',(-36.5921969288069,-10.6340822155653,-132.3052368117));
#541=CARTESIAN_POINT('',(-40.782660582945,-11.9357265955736,-133.726129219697));
#542=CARTESIAN_POINT('',(-36.4128083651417,-11.2243216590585,-127.597597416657));
#543=CARTESIAN_POINT('',(-36.2783084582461,-11.6615534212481,-132.211827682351));
#544=CARTESIAN_POINT('',(-40.4586759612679,-13.0950419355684,-133.61675944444));
#545=CARTESIAN_POINT('',(-36.2569722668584,-11.7179114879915,-127.536606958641));
#546=CARTESIAN_POINT('',(-36.1106588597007,-12.1714276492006,-132.162273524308));
#547=CARTESIAN_POINT('',(-40.2855247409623,-13.6708967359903,-133.558673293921));
#548=CARTESIAN_POINT('',(-36.0912363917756,-12.2078931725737,-127.472255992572));
#549=CARTESIAN_POINT('',(-35.9327782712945,-12.6763564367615,-132.110143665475));
#550=CARTESIAN_POINT('',(-40.1013737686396,-14.2425420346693,-133.497386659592));
#551=(BOUNDED_SURFACE() B_SPLINE_SURFACE(3,2,((#239,#240,#241),(#242,#243,#244),(#245,#246,
#247),(#248,#249,#250),(#251,#252,#253),(#254,#255,#256),(#257,#258,#259),(#260,#261,#262),
(#263,#264,#265),(#266,#267,#268),(#269,#270,#271),(#272,#273,#274),(#275,#276,#277),(#278,#279,
#280),(#281,#282,#283),(#284,#285,#286),(#287,#288,#289),(#290,#291,#292),(#293,#294,#295),
(#296,#297,#298),(#299,#300,#301),(#302,#303,#304),(#305,#306,#307),(#308,#309,#310),(#311,#312,
#313),(#314,#315,#316),(#317,#318,#319),(#320,#321,#322),(#323,#324,#325),(#326,#327,#328),
(#329,#330,#331),(#332,#333,#334),(#335,#336,#337),(#338,#339,#340),(#341,#342,#343),(#344,#345,
#346),(#347,#348,#349),(#350,#351,#352),(#353,#354,#355),(#356,#357,#358),(#359,#360,#361),
(#362,#363,#364),(#365,#366,#367),(#368,#369,#370),(#371,#372,#373),(#374,#375,#376),(#377,#378,
#379),(#380,#381,#382),(#383,#384,#385),(#386,#387,#388),(#389,#390,#391),(#392,#393,#394),
(#395,#396,#397),(#398,#399,#400),(#401,#402,#403),(#404,#405,#406),(#407,#408,#409),(#410,#411,
#412),(#413,#414,#415),(#416,#417,#418),(#419,#420,#421),(#422,#423,#424),(#425,#426,#427),
(#428,#429,#430),(#431,#432,#433),(#434,#435,#436),(#437,#438,#439),(#440,#441,#442),(#443,#444,
#445),(#446,#447,#448),(#449,#450,#451),(#452,#453,#454),(#455,#456,#457),(#458,#459,#460),
(#461,#462,#463),(#464,#465,#466),(#467,#468,#469),(#470,#471,#472),(#473,#474,#475),(#476,#477,
#478),(#479,#480,#481),(#482,#483,#484),(#485,#486,#487),(#488,#489,#490),(#491,#492,#493),
(#494,#495,#496),(#497,#498,#499),(#500,#501,#502),(#503,#504,#505),(#506,#507,#508),(#509,#510,
#511),(#512,#513,#514),(#515,#516,#517),(#518,#519,#520),(#521,#522,#523),(#524,#525,#526),
(#527,#528,#529),(#530,#531,#532),(#533,#534,#535),(#536,#537,#538),(#539,#540,#541),(#542,#543,
#544),(#545,#546,#547),(#548,#549,#550)),.UNSPECIFIED.,.F.,.F.,
.F.) B_SPLINE_SURFACE_WITH_KNOTS((4,2,2,2,2,2,2,2,2,2,2,2,2,2,2,2,2,2,2,2,2,2,2,2,2,2,2,2,2,2,2,
2,2,2,2,2,2,2,2,2,2,2,2,2,2,2,2,2,2,2,2,4),(3,3),(0.,1.81701540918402,3.63407989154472,
7.26772663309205,10.8959222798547,14.5238513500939,18.1549800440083,21.7862281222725,
25.4165695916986,29.0468936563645,32.6701181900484,36.2933473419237,39.9180919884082,
43.5430585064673,47.2964541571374,51.0499287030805,54.8036556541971,58.5572699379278,
62.4092952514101,66.261407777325,70.1128392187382,73.9641057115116,77.6813434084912,
81.3985025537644,85.1148110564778,88.8310335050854,92.4012784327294,95.9714131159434,
99.5417060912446,103.112078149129,106.72934596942,110.346628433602,113.964523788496,
117.58255595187,121.370519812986,125.158626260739,128.948605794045,130.843690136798,
132.739324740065,136.586042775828,140.432590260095,142.353370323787,144.273643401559,
148.111959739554,151.631973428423,153.391008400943,155.150419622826,158.770019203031,
162.391538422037,166.033471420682,167.853906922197,169.674275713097),(0.,1.),
.UNSPECIFIED.) GEOMETRIC_REPRESENTATION_ITEM() RATIONAL_B_SPLINE_SURFACE(((1.,0.805950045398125,
1.),(1.,0.806800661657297,1.),(1.,0.807604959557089,1.),(1.,0.809116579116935,1.),(1.,
0.809823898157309,1.),(1.,0.811793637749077,1.),(1.,0.812904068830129,1.),(1.,0.814689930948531,
1.),(1.,0.815366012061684,1.),(1.,0.816269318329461,1.),(1.,0.816496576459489,1.),(1.,
0.816496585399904,1.),(1.,0.816268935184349,1.),(1.,0.81536402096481,1.),(1.,0.814686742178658,
1.),(1.,0.812899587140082,1.),(1.,0.811789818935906,1.),(1.,0.80916486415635,1.),(1.,
0.807649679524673,1.),(1.,0.804253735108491,1.),(1.,0.802373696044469,1.),(1.,0.798290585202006,
1.),(1.,0.796087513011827,1.),(1.,0.79140879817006,1.),(1.,0.788933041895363,1.),(1.,
0.783767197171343,1.),(1.,0.781077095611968,1.),(1.,0.775447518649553,1.),(1.,0.772502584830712,
1.),(1.,0.766525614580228,1.),(1.,0.763493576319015,1.),(1.,0.757421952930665,1.),(1.,
0.754382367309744,1.),(1.,0.748379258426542,1.),(1.,0.745415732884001,1.),(1.,0.739574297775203,
1.),(1.,0.736700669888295,1.),(1.,0.731215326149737,1.),(1.,0.728603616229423,1.),(1.,
0.723731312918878,1.),(1.,0.721470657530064,1.),(1.,0.717381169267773,1.),(1.,0.7155523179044,
1.),(1.,0.712450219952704,1.),(1.,0.711159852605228,1.),(1.,0.709092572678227,1.),(1.,
0.708315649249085,1.),(1.,0.707304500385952,1.),(1.,0.707070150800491,1.),(1.,0.707152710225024,
1.),(1.,0.707469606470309,1.),(1.,0.708619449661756,1.),(1.,0.709431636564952,1.),(1.,
0.711525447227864,1.),(1.,0.712807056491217,1.),(1.,0.715796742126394,1.),(1.,0.717504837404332,
1.),(1.,0.721292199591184,1.),(1.,0.723371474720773,1.),(1.,0.727866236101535,1.),(1.,
0.730285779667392,1.),(1.,0.735366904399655,1.),(1.,0.73802848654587,1.),(1.,0.743518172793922,
1.),(1.,0.746346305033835,1.),(1.,0.752092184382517,1.),(1.,0.755009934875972,1.),(1.,
0.760997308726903,1.),(1.,0.764067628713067,1.),(1.,0.770140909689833,1.),(1.,0.773143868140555,
1.),(1.,0.779005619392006,1.),(1.,0.781864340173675,1.),(1.,0.785987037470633,1.),(1.,
0.787333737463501,1.),(1.,0.789964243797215,1.),(1.,0.791248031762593,1.),(1.,0.795028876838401,
1.),(1.,0.797414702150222,1.),(1.,0.801828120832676,1.),(1.,0.803855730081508,1.),(1.,
0.806586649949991,1.),(1.,0.807444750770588,1.),(1.,0.809052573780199,1.),(1.,0.809802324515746,
1.),(1.,0.811880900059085,1.),(1.,0.81304011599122,1.),(1.,0.814797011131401,1.),(1.,
0.815433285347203,1.),(1.,0.816070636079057,1.),(1.,0.816230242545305,1.),(1.,0.816443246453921,
1.),(1.,0.816496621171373,1.),(1.,0.81649649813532,1.),(1.,0.816270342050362,1.),(1.,
0.815371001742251,1.),(1.,0.814697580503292,1.),(1.,0.812914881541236,1.),(1.,0.811803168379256,
1.),(1.,0.809830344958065,1.),(1.,0.809121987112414,1.),(1.,0.80760792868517,1.),(1.,
0.806802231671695,1.),(1.,0.805950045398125,1.))) REPRESENTATION_ITEM('') SURFACE());
#552=CARTESIAN_POINT('',(36.0912363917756,-12.2078931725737,-127.472255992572));
#553=CARTESIAN_POINT('',(36.2566669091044,-11.7188156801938,-127.536488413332));
#554=CARTESIAN_POINT('',(36.4122340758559,-11.2261412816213,-127.597372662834));
#555=CARTESIAN_POINT('',(36.7033555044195,-10.2343004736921,-127.712025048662));
#556=CARTESIAN_POINT('',(36.838909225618,-9.73513388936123,-127.765792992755));
#557=CARTESIAN_POINT('',(37.2150749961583,-8.22912180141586,-127.915774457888));
#558=CARTESIAN_POINT('',(37.4252357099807,-7.21363378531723,-128.000682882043));
#559=CARTESIAN_POINT('',(37.7619395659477,-5.1689618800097,-128.137495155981));
#560=CARTESIAN_POINT('',(37.8886076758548,-4.13980082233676,-128.189448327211));
#561=CARTESIAN_POINT('',(38.0576344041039,-2.07375805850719,-128.258906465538));
#562=CARTESIAN_POINT('',(38.0999992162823,-1.03687692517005,-128.276413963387));
#563=CARTESIAN_POINT('',(38.1000007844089,1.03779139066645,-128.276414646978));
#564=CARTESIAN_POINT('',(38.0575627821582,2.07557856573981,-128.258876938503));
#565=CARTESIAN_POINT('',(37.8882350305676,4.14340805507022,-128.189295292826));
#566=CARTESIAN_POINT('',(37.7613425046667,5.17345011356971,-128.137250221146));
#567=CARTESIAN_POINT('',(37.4243865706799,7.21792363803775,-128.000340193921));
#568=CARTESIAN_POINT('',(37.2143439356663,8.23235893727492,-127.915483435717));
#569=CARTESIAN_POINT('',(36.7130537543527,10.2386960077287,-127.715612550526));
#570=CARTESIAN_POINT('',(36.4218065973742,11.2305978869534,-127.600598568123));
#571=CARTESIAN_POINT('',(35.7613126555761,13.1832772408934,-127.344164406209));
#572=CARTESIAN_POINT('',(35.3922195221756,14.1441117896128,-127.202796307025));
#573=CARTESIAN_POINT('',(34.5786856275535,16.0305867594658,-126.897639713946));
#574=CARTESIAN_POINT('',(34.1342447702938,16.9562271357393,-126.733851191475));
#575=CARTESIAN_POINT('',(33.1731253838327,18.767125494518,-126.388388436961));
#576=CARTESIAN_POINT('',(32.656416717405,19.6523664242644,-126.206706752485));
#577=CARTESIAN_POINT('',(31.5544193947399,21.376995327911,-125.830432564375));
#578=CARTESIAN_POINT('',(30.9691265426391,22.216380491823,-125.635839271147));
#579=CARTESIAN_POINT('',(29.7117893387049,23.8733988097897,-125.231814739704));
#580=CARTESIAN_POINT('',(29.0374061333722,24.6892076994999,-125.022102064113));
#581=CARTESIAN_POINT('',(27.623414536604,26.2616647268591,-124.60004915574));
#582=CARTESIAN_POINT('',(26.8838047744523,27.018311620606,-124.387708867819));
#583=CARTESIAN_POINT('',(25.3438370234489,28.4678436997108,-123.966087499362));
#584=CARTESIAN_POINT('',(24.5434749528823,29.1607245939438,-123.756806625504));
#585=CARTESIAN_POINT('',(22.8868938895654,30.4781898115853,-123.346891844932));
#586=CARTESIAN_POINT('',(22.0306765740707,31.1027761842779,-123.146257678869));
#587=CARTESIAN_POINT('',(20.2444054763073,32.2948436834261,-122.753882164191));
#588=CARTESIAN_POINT('',(19.313004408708,32.8603983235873,-122.562511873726));
#589=CARTESIAN_POINT('',(17.4029087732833,33.9107160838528,-122.199890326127));
#590=CARTESIAN_POINT('',(16.4242131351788,34.3954773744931,-122.0286395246));
#591=CARTESIAN_POINT('',(14.4264482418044,35.2800326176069,-121.711196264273));
#592=CARTESIAN_POINT('',(13.40738615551,35.6798415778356,-121.56499938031));
#593=CARTESIAN_POINT('',(11.3361359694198,36.3909438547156,-121.301900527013));
#594=CARTESIAN_POINT('',(10.2839492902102,36.7022409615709,-121.184997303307));
#595=CARTESIAN_POINT('',(8.19154249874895,37.2240578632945,-120.987455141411));
#596=CARTESIAN_POINT('',(7.15218026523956,37.4377078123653,-120.905695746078));
#597=CARTESIAN_POINT('',(5.05776764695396,37.777697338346,-120.775000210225));
#598=CARTESIAN_POINT('',(4.00271759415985,37.9040387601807,-120.72606337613));
#599=CARTESIAN_POINT('',(1.88523628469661,38.0681403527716,-120.662415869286));
#600=CARTESIAN_POINT('',(0.822806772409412,38.1059207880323,-120.647697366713));
#601=CARTESIAN_POINT('',(-1.30141903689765,38.0925761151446,-120.652887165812));
#602=CARTESIAN_POINT('',(-2.36321534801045,38.0414530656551,-120.67279466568));
#603=CARTESIAN_POINT('',(-4.43637562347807,37.8545764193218,-120.745206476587));
#604=CARTESIAN_POINT('',(-5.44808226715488,37.72222609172,-120.796399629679));
#605=CARTESIAN_POINT('',(-7.45619165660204,37.3771728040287,-120.928859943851));
#606=CARTESIAN_POINT('',(-8.45259487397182,37.1644723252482,-121.010126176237));
#607=CARTESIAN_POINT('',(-10.4233648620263,36.6605785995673,-121.200627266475));
#608=CARTESIAN_POINT('',(-11.3977306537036,36.3693818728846,-121.309863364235));
#609=CARTESIAN_POINT('',(-13.3180269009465,35.7109297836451,-121.553511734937));
#610=CARTESIAN_POINT('',(-14.2639567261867,35.3436727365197,-121.687924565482));
#611=CARTESIAN_POINT('',(-16.1336707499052,34.5306746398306,-121.980461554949));
#612=CARTESIAN_POINT('',(-17.0570008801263,34.083966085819,-122.13887396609));
#613=CARTESIAN_POINT('',(-18.8627678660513,33.118788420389,-122.474065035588));
#614=CARTESIAN_POINT('',(-19.7452045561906,32.6003190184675,-122.650843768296));
#615=CARTESIAN_POINT('',(-21.4641863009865,31.4951262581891,-123.018387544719));
#616=CARTESIAN_POINT('',(-22.3007235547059,30.908391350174,-123.209154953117));
#617=CARTESIAN_POINT('',(-23.9230317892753,29.6705195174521,-123.599934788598));
#618=CARTESIAN_POINT('',(-24.708800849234,29.0193801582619,-123.799947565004));
#619=CARTESIAN_POINT('',(-26.2608053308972,27.6246091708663,-124.21378311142));
#620=CARTESIAN_POINT('',(-27.0243898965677,26.8780697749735,-124.427813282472));
#621=CARTESIAN_POINT('',(-28.4863430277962,25.3234486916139,-124.854762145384));
#622=CARTESIAN_POINT('',(-29.1847091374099,24.5153646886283,-125.067680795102));
#623=CARTESIAN_POINT('',(-30.5121453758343,22.8420588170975,-125.486638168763));
#624=CARTESIAN_POINT('',(-31.1411810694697,21.9768088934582,-125.692673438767));
#625=CARTESIAN_POINT('',(-32.0289964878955,20.6407247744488,-125.992004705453));
#626=CARTESIAN_POINT('',(-32.3156517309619,20.1889834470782,-126.090163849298));
#627=CARTESIAN_POINT('',(-32.870024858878,19.2732461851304,-126.282579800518));
#628=CARTESIAN_POINT('',(-33.1377372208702,18.8092467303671,-126.376835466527));
#629=CARTESIAN_POINT('',(-33.9191888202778,17.3862307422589,-126.65536178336));
#630=CARTESIAN_POINT('',(-34.4025483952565,16.4092586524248,-126.832430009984));
#631=CARTESIAN_POINT('',(-35.2846913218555,14.4148977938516,-127.161840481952));
#632=CARTESIAN_POINT('',(-35.6834784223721,13.3975108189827,-127.314183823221));
#633=CARTESIAN_POINT('',(-36.2152196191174,11.8476108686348,-127.520298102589));
#634=CARTESIAN_POINT('',(-36.3813070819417,11.3273532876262,-127.585234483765));
#635=CARTESIAN_POINT('',(-36.6910920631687,10.2796937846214,-127.70715891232));
#636=CARTESIAN_POINT('',(-36.8347954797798,9.75229378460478,-127.764149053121));
#637=CARTESIAN_POINT('',(-37.2317268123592,8.16105390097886,-127.922421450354));
#638=CARTESIAN_POINT('',(-37.4509821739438,7.08757292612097,-128.011086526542));
#639=CARTESIAN_POINT('',(-37.7820230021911,5.01379669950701,-128.145719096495));
#640=CARTESIAN_POINT('',(-37.9012128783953,4.01481465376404,-128.194617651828));
#641=CARTESIAN_POINT('',(-38.0204475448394,2.51160892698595,-128.243631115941));
#642=CARTESIAN_POINT('',(-38.0502673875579,2.00989086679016,-128.255913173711));
#643=CARTESIAN_POINT('',(-38.0900477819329,1.00547079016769,-128.272307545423));
#644=CARTESIAN_POINT('',(-38.1000040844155,0.502768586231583,-128.276418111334));
#645=CARTESIAN_POINT('',(-38.0999915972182,-1.03433520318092,-128.276406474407));
#646=CARTESIAN_POINT('',(-38.0578268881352,-2.06895136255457,-128.258984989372));
#647=CARTESIAN_POINT('',(-37.8895404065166,-4.13083911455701,-128.189832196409));
#648=CARTESIAN_POINT('',(-37.7633741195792,-5.15810652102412,-128.138082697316));
#649=CARTESIAN_POINT('',(-37.4272819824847,-7.20333606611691,-128.001509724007));
#650=CARTESIAN_POINT('',(-37.2168880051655,-8.22121311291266,-127.916501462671));
#651=CARTESIAN_POINT('',(-36.840143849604,-9.7305135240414,-127.766283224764));
#652=CARTESIAN_POINT('',(-36.7043945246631,-10.2306227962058,-127.712435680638));
#653=CARTESIAN_POINT('',(-36.4128083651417,-11.2243216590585,-127.597597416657));
#654=CARTESIAN_POINT('',(-36.2569722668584,-11.7179114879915,-127.536606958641));
#655=CARTESIAN_POINT('',(-36.0912363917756,-12.2078931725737,-127.472255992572));
#656=B_SPLINE_CURVE_WITH_KNOTS('',3,(#552,#553,#554,#555,#556,#557,#558,#559,#560,#561,#562,
#563,#564,#565,#566,#567,#568,#569,#570,#571,#572,#573,#574,#575,#576,#577,#578,#579,#580,#581,
#582,#583,#584,#585,#586,#587,#588,#589,#590,#591,#592,#593,#594,#595,#596,#597,#598,#599,#600,
#601,#602,#603,#604,#605,#606,#607,#608,#609,#610,#611,#612,#613,#614,#615,#616,#617,#618,#619,
#620,#621,#622,#623,#624,#625,#626,#627,#628,#629,#630,#631,#632,#633,#634,#635,#636,#637,#638,
#639,#640,#641,#642,#643,#644,#645,#646,#647,#648,#649,#650,#651,#652,#653,#654,#655),
.UNSPECIFIED.,.F.,.F.,(4,2,2,2,2,2,2,2,2,2,2,2,2,2,2,2,2,2,2,2,2,2,2,2,2,2,2,2,2,2,2,2,2,2,2,2,
2,2,2,2,2,2,2,2,2,2,2,2,2,2,2,4),(0.,1.81701540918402,3.63407989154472,7.26772663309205,
10.8959222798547,14.5238513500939,18.1549800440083,21.7862281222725,25.4165695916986,
29.0468936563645,32.6701181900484,36.2933473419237,39.9180919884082,43.5430585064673,
47.2964541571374,51.0499287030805,54.8036556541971,58.5572699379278,62.4092952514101,
66.261407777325,70.1128392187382,73.9641057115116,77.6813434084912,81.3985025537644,
85.1148110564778,88.8310335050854,92.4012784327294,95.9714131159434,99.5417060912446,
103.112078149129,106.72934596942,110.346628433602,113.964523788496,117.58255595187,
121.370519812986,125.158626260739,128.948605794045,130.843690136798,132.739324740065,
136.586042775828,140.432590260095,142.353370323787,144.273643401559,148.111959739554,
151.631973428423,153.391008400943,155.150419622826,158.770019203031,162.391538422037,
166.033471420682,167.853906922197,169.674275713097),.UNSPECIFIED.);
#657=CARTESIAN_POINT('',(38.1,0.,-128.276414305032));
#658=VERTEX_POINT('',#657);
#659=CARTESIAN_POINT('',(-38.1,0.,-128.276414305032));
#660=VERTEX_POINT('',#659);
#661=EDGE_CURVE('E72',#658,#660,#656,.T.);
#662=ORIENTED_EDGE('',*,*,#661,.T.);
#663=CARTESIAN_POINT('',(0.,0.,-128.276414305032));
#664=DIRECTION('',(0.,0.,-1.));
#665=DIRECTION('',(-1.,0.,0.));
#666=AXIS2_PLACEMENT_3D('',#663,#664,#665);
#667=CIRCLE('',#666,38.1);
#668=EDGE_CURVE('E67',#660,#658,#667,.F.);
#669=ORIENTED_EDGE('',*,*,#668,.T.);
#670=EDGE_LOOP('',(#662,#669));
#671=FACE_BOUND('',#670,.T.);
#672=ADVANCED_FACE('F77',(#238,#671),#227,.T.);
#673=CARTESIAN_POINT('',(0.,0.,-254.));
#674=DIRECTION('',(0.,-1.,0.));
#675=DIRECTION('',(-1.,0.,0.));
#676=AXIS2_PLACEMENT_3D('',#673,#674,#675);
#677=SPHERICAL_SURFACE('',#676,127.);
#678=CARTESIAN_POINT('',(0.,0.,-254.));
#679=DIRECTION('',(0.,-1.,0.));
#680=DIRECTION('',(1.,0.,0.));
#681=AXIS2_PLACEMENT_3D('',#678,#679,#680);
#682=CIRCLE('',#681,127.);
#683=CARTESIAN_POINT('',(-42.3333333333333,0.,-134.263251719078));
#684=VERTEX_POINT('',#683);
#685=CARTESIAN_POINT('',(42.3333333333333,0.,-134.263251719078));
#686=VERTEX_POINT('',#685);
#687=EDGE_CURVE('E125',#684,#686,#682,.T.);
#688=ORIENTED_EDGE('',*,*,#687,.T.);
#689=CARTESIAN_POINT('',(0.,0.,-134.263251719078));
#690=DIRECTION('',(0.,0.,-1.));
#691=DIRECTION('',(-1.,0.,0.));
#692=AXIS2_PLACEMENT_3D('',#689,#690,#691);
#693=CIRCLE('',#692,42.3333333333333);
#694=EDGE_CURVE('E43',#686,#684,#693,.T.);
#695=ORIENTED_EDGE('',*,*,#694,.T.);
#696=EDGE_LOOP('',(#688,#695));
#697=FACE_BOUND('',#696,.T.);
#698=ADVANCED_FACE('F258',(#697),#677,.T.);
#699=CARTESIAN_POINT('',(0.,381.,-254.));
#700=DIRECTION('',(0.,-1.,0.));
#701=DIRECTION('',(1.,0.,0.));
#702=AXIS2_PLACEMENT_3D('',#699,#700,#701);
#703=CYLINDRICAL_SURFACE('',#702,127.);
#704=CARTESIAN_POINT('',(0.,762.,-254.));
#705=DIRECTION('',(0.,-1.,0.));
#706=DIRECTION('',(1.,0.,0.));
#707=AXIS2_PLACEMENT_3D('',#704,#705,#706);
#708=CIRCLE('',#707,127.);
#709=CARTESIAN_POINT('',(127.,762.,-254.));
#710=VERTEX_POINT('',#709);
#711=EDGE_CURVE('E123',#710,#710,#708,.T.);
#712=ORIENTED_EDGE('',*,*,#711,.T.);
#713=EDGE_LOOP('',(#712));
#714=FACE_BOUND('',#713,.T.);
#715=ORIENTED_EDGE('',*,*,#687,.F.);
#716=CARTESIAN_POINT('',(-40.1013737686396,-14.2425420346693,-133.497386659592));
#717=CARTESIAN_POINT('',(-40.2855247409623,-13.6708967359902,-133.558673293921));
#718=CARTESIAN_POINT('',(-40.4586759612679,-13.0950419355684,-133.61675944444));
#719=CARTESIAN_POINT('',(-40.782660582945,-11.9357265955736,-133.726129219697));
#720=CARTESIAN_POINT('',(-40.9334931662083,-11.3522657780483,-133.777412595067));
#721=CARTESIAN_POINT('',(-41.3520977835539,-9.59141529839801,-133.920477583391));
#722=CARTESIAN_POINT('',(-41.5858688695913,-8.40389207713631,-134.00143783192));
#723=CARTESIAN_POINT('',(-41.9593045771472,-6.01779094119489,-134.131507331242));
#724=CARTESIAN_POINT('',(-42.09948933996,-4.81931230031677,-134.180792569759));
#725=CARTESIAN_POINT('',(-42.286474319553,-2.41377658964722,-134.246652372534));
#726=CARTESIAN_POINT('',(-42.3333239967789,-1.2067244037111,-134.263244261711));
#727=CARTESIAN_POINT('',(-42.333337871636,0.586563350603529,-134.263255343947));
#728=CARTESIAN_POINT('',(-42.3222753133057,1.17304925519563,-134.259340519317));
#729=CARTESIAN_POINT('',(-42.2780748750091,2.34487267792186,-134.243726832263));
#730=CARTESIAN_POINT('',(-42.244941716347,2.93021041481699,-134.232029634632));
#731=CARTESIAN_POINT('',(-42.1124587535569,4.68395042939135,-134.18535014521));
#732=CARTESIAN_POINT('',(-41.9800255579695,5.84942948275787,-134.138780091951));
#733=CARTESIAN_POINT('',(-41.6122024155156,8.26883508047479,-134.01055859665));
#734=CARTESIAN_POINT('',(-41.3685853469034,9.52122955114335,-133.926115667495));
#735=CARTESIAN_POINT('',(-40.9275505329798,11.3776760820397,-133.775380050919));
#736=CARTESIAN_POINT('',(-40.7678800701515,11.9929760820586,-133.721103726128));
#737=CARTESIAN_POINT('',(-40.4236745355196,13.2152455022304,-133.604985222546));
#738=CARTESIAN_POINT('',(-40.239132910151,13.8222126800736,-133.54314105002));
#739=CARTESIAN_POINT('',(-39.6483093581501,15.6304292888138,-133.346841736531));
#740=CARTESIAN_POINT('',(-39.2052125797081,16.8173807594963,-133.201752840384));
#741=CARTESIAN_POINT('',(-38.2250537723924,19.1441350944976,-132.888028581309));
#742=CARTESIAN_POINT('',(-37.6879875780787,20.2839358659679,-132.719392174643));
#743=CARTESIAN_POINT('',(-36.8197080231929,21.9441211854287,-132.454129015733));
#744=CARTESIAN_POINT('',(-36.5222498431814,22.4854538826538,-132.364361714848));
#745=CARTESIAN_POINT('',(-35.9062797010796,23.5538140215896,-132.181108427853));
#746=CARTESIAN_POINT('',(-35.5877738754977,24.0808455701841,-132.087623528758));
#747=CARTESIAN_POINT('',(-34.6013122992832,25.6396103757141,-131.802546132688));
#748=CARTESIAN_POINT('',(-33.9023837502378,26.6490686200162,-131.606322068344));
#749=CARTESIAN_POINT('',(-32.427454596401,28.6012588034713,-131.207315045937));
#750=CARTESIAN_POINT('',(-31.6514922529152,29.5440234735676,-131.004535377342));
#751=CARTESIAN_POINT('',(-30.0270998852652,31.3577480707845,-130.597917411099));
#752=CARTESIAN_POINT('',(-29.1786725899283,32.2287106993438,-130.394079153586));
#753=CARTESIAN_POINT('',(-27.4542231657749,33.8559435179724,-129.99995006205));
#754=CARTESIAN_POINT('',(-26.5811464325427,34.6156061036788,-129.809461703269));
#755=CARTESIAN_POINT('',(-24.7785817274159,36.0597899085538,-129.437290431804));
#756=CARTESIAN_POINT('',(-23.8490958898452,36.7443139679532,-129.255607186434));
#757=CARTESIAN_POINT('',(-21.9391161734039,38.0337055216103,-128.905565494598));
#758=CARTESIAN_POINT('',(-20.9586309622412,38.6385864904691,-128.737204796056));
#759=CARTESIAN_POINT('',(-18.9522232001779,39.7646271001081,-128.417975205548));
#760=CARTESIAN_POINT('',(-17.9263008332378,40.2857870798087,-128.267106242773));
#761=CARTESIAN_POINT('',(-15.8488408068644,41.2342848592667,-127.988499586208));
#762=CARTESIAN_POINT('',(-14.7978076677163,41.662751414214,-127.860487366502));
#763=CARTESIAN_POINT('',(-12.6641451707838,42.4309455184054,-127.628441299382));
#764=CARTESIAN_POINT('',(-11.5815165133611,42.7706750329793,-127.524406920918));
#765=CARTESIAN_POINT('',(-9.39177208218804,43.3585510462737,-127.342977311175));
#766=CARTESIAN_POINT('',(-8.28465739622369,43.6067016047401,-127.26558089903));
#767=CARTESIAN_POINT('',(-6.05342474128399,44.0092637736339,-127.139428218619));
#768=CARTESIAN_POINT('',(-4.92930624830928,44.1636724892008,-127.090672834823));
#769=CARTESIAN_POINT('',(-2.6257948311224,44.3816952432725,-127.021709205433));
#770=CARTESIAN_POINT('',(-1.44602115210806,44.4413388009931,-127.002749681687));
#771=CARTESIAN_POINT('',(0.914229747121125,44.4569075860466,-126.997807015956));
#772=CARTESIAN_POINT('',(2.09470698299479,44.4128304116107,-127.011824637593));
#773=CARTESIAN_POINT('',(4.44746399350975,44.2213785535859,-127.07244131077));
#774=CARTESIAN_POINT('',(5.61974182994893,44.073980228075,-127.119047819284));
#775=CARTESIAN_POINT('',(7.94686696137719,43.6773257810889,-127.243519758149));
#776=CARTESIAN_POINT('',(9.10171388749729,43.4280675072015,-127.321385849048));
#777=CARTESIAN_POINT('',(11.4266103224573,42.8192811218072,-127.509521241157));
#778=CARTESIAN_POINT('',(12.5957066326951,42.4561011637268,-127.620857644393));
#779=CARTESIAN_POINT('',(14.8970957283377,41.6264818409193,-127.871427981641));
#780=CARTESIAN_POINT('',(16.0293869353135,41.1600380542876,-128.010663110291));
#781=CARTESIAN_POINT('',(18.2491257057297,40.1280569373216,-128.312990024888));
#782=CARTESIAN_POINT('',(19.3365653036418,39.5625020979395,-128.476086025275));
#783=CARTESIAN_POINT('',(21.4588937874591,38.3371313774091,-128.821439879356));
#784=CARTESIAN_POINT('',(22.4937838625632,37.6773176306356,-129.003697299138));
#785=CARTESIAN_POINT('',(24.4785295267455,36.2865722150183,-129.377388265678));
#786=CARTESIAN_POINT('',(25.429882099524,35.5578881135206,-129.568468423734));
#787=CARTESIAN_POINT('',(27.2705277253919,34.0208453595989,-129.958863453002));
#788=CARTESIAN_POINT('',(28.1598189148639,33.2124843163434,-130.158178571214));
#789=CARTESIAN_POINT('',(29.8708941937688,31.5213635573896,-130.559722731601));
#790=CARTESIAN_POINT('',(30.6926828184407,30.6386088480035,-130.76195157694));
#791=CARTESIAN_POINT('',(32.2637845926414,28.8040756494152,-131.163906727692));
#792=CARTESIAN_POINT('',(33.0130992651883,27.852298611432,-131.363633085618));
#793=CARTESIAN_POINT('',(34.4101406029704,25.9191105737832,-131.748418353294));
#794=CARTESIAN_POINT('',(35.06046599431,24.9398278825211,-131.933745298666));
#795=CARTESIAN_POINT('',(36.2849074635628,22.9277608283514,-132.292101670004));
#796=CARTESIAN_POINT('',(36.8590282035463,21.8949797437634,-132.465131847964));
#797=CARTESIAN_POINT('',(37.9269386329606,19.7822649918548,-132.794143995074));
#798=CARTESIAN_POINT('',(38.4207618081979,18.7023512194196,-132.950133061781));
#799=CARTESIAN_POINT('',(39.3246883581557,16.5014637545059,-133.240758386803));
#800=CARTESIAN_POINT('',(39.7347918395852,15.3804901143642,-133.375394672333));
#801=CARTESIAN_POINT('',(40.4686739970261,13.1023642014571,-133.619617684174));
#802=CARTESIAN_POINT('',(40.792281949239,11.9451453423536,-133.729154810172));
#803=CARTESIAN_POINT('',(41.3492710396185,9.60441876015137,-133.919508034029));
#804=CARTESIAN_POINT('',(41.5826517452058,8.42091091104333,-134.000323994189));
#805=CARTESIAN_POINT('',(41.9570472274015,6.03569179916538,-134.130714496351));
#806=CARTESIAN_POINT('',(42.0980389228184,4.83397606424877,-134.180281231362));
#807=CARTESIAN_POINT('',(42.2861808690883,2.42150832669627,-134.246549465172));
#808=CARTESIAN_POINT('',(42.3333342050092,1.2107566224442,-134.263252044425));
#809=CARTESIAN_POINT('',(42.3333324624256,-1.20968974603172,-134.263251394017));
#810=CARTESIAN_POINT('',(42.286260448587,-2.41938440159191,-134.246577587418));
#811=CARTESIAN_POINT('',(42.0984529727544,-4.82976762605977,-134.180426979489));
#812=CARTESIAN_POINT('',(41.9577106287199,-6.03045552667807,-134.130947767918));
#813=CARTESIAN_POINT('',(41.583595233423,-8.41590608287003,-134.000650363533));
#814=CARTESIAN_POINT('',(41.3500833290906,-9.60064210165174,-133.919785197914));
#815=CARTESIAN_POINT('',(40.9321213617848,-11.3576562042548,-133.776945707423));
#816=CARTESIAN_POINT('',(40.7815061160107,-11.9400172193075,-133.725738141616));
#817=CARTESIAN_POINT('',(40.4580378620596,-13.0971648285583,-133.616545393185));
#818=CARTESIAN_POINT('',(40.2851854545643,-13.6719516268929,-133.558560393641));
#819=CARTESIAN_POINT('',(40.1013737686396,-14.2425420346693,-133.497386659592));
#820=B_SPLINE_CURVE_WITH_KNOTS('',3,(#716,#717,#718,#719,#720,#721,#722,#723,#724,#725,#726,
#727,#728,#729,#730,#731,#732,#733,#734,#735,#736,#737,#738,#739,#740,#741,#742,#743,#744,#745,
#746,#747,#748,#749,#750,#751,#752,#753,#754,#755,#756,#757,#758,#759,#760,#761,#762,#763,#764,
#765,#766,#767,#768,#769,#770,#771,#772,#773,#774,#775,#776,#777,#778,#779,#780,#781,#782,#783,
#784,#785,#786,#787,#788,#789,#790,#791,#792,#793,#794,#795,#796,#797,#798,#799,#800,#801,#802,
#803,#804,#805,#806,#807,#808,#809,#810,#811,#812,#813,#814,#815,#816,#817,#818,#819),
.UNSPECIFIED.,.F.,.F.,(4,2,2,2,2,2,2,2,2,2,2,2,2,2,2,2,2,2,2,2,2,2,2,2,2,2,2,2,2,2,2,2,2,2,2,2,
2,2,2,2,2,2,2,2,2,2,2,2,2,2,2,4),(0.,1.82036879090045,3.64080429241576,7.28273729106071,
10.9042565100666,14.5238560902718,16.2832673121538,18.0423022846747,21.5623159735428,
25.4006323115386,27.3209053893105,29.2416854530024,33.088232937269,36.9349509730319,
38.8305855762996,40.7256699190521,44.5156494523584,48.3037559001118,52.0917197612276,
55.7097519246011,59.3276472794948,62.9449297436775,66.5621975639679,70.1325696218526,
73.7028625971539,77.2729972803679,80.8432422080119,84.5594646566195,88.2757731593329,
91.9929323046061,95.7101700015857,99.5614364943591,103.412867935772,107.264980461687,
111.11700577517,114.8706200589,118.624347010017,122.37782155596,126.13121720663,
129.756183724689,133.380928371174,137.004157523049,140.627382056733,144.257706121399,
147.888047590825,151.519295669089,155.150424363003,158.778353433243,162.406549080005,
166.040195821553,167.857260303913,169.674275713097),.UNSPECIFIED.);
#821=EDGE_CURVE('E11',#684,#686,#820,.T.);
#822=ORIENTED_EDGE('',*,*,#821,.T.);
#823=EDGE_LOOP('',(#715,#822));
#824=FACE_BOUND('',#823,.T.);
#825=ADVANCED_FACE('F100',(#714,#824),#703,.T.);
#826=CARTESIAN_POINT('',(0.,762.,-254.));
#827=DIRECTION('',(0.,-1.,0.));
#828=DIRECTION('',(-1.,0.,0.));
#829=AXIS2_PLACEMENT_3D('',#826,#827,#828);
#830=SPHERICAL_SURFACE('',#829,127.);
#831=ORIENTED_EDGE('',*,*,#711,.F.);
#832=EDGE_LOOP('',(#831));
#833=FACE_BOUND('',#832,.T.);
#834=ADVANCED_FACE('F237',(#833),#830,.T.);
#835=CARTESIAN_POINT('',(0.,0.,-6.34999999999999));
#836=DIRECTION('',(0.,0.,1.));
#837=DIRECTION('',(1.,0.,0.));
#838=AXIS2_PLACEMENT_3D('',#835,#836,#837);
#839=TOROIDAL_SURFACE('',#838,44.45,6.35);
#840=ORIENTED_EDGE('',*,*,#31,.F.);
#841=EDGE_LOOP('',(#840));
#842=FACE_BOUND('',#841,.T.);
#843=ORIENTED_EDGE('',*,*,#235,.F.);
#844=EDGE_LOOP('',(#843));
#845=FACE_BOUND('',#844,.T.);
#846=ADVANCED_FACE('F109',(#842,#845),#839,.F.);
#847=CARTESIAN_POINT('',(44.45,0.,-128.276414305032));
#848=DIRECTION('',(0.,1.,0.));
#849=DIRECTION('',(-1.,0.,0.));
#850=AXIS2_PLACEMENT_3D('',#847,#848,#849);
#851=CIRCLE('',#850,6.35);
#852=EDGE_CURVE('E63',#686,#658,#851,.T.);
#853=ORIENTED_EDGE('',*,*,#852,.F.);
#854=ORIENTED_EDGE('',*,*,#821,.F.);
#855=CARTESIAN_POINT('',(-44.45,0.,-128.276414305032));
#856=DIRECTION('',(0.,1.,0.));
#857=DIRECTION('',(-1.,0.,0.));
#858=AXIS2_PLACEMENT_3D('',#855,#856,#857);
#859=CIRCLE('',#858,6.35);
#860=EDGE_CURVE('E56',#660,#684,#859,.T.);
#861=ORIENTED_EDGE('',*,*,#860,.F.);
#862=ORIENTED_EDGE('',*,*,#661,.F.);
#863=EDGE_LOOP('',(#853,#854,#861,#862));
#864=FACE_BOUND('',#863,.T.);
#865=ADVANCED_FACE('F73',(#864),#551,.F.);
#866=CARTESIAN_POINT('',(0.,0.,-128.276414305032));
#867=DIRECTION('',(0.,0.,-1.));
#868=DIRECTION('',(-1.,0.,0.));
#869=AXIS2_PLACEMENT_3D('',#866,#867,#868);
#870=TOROIDAL_SURFACE('',#869,44.45,6.35);
#871=ORIENTED_EDGE('',*,*,#860,.T.);
#872=ORIENTED_EDGE('',*,*,#694,.F.);
#873=ORIENTED_EDGE('',*,*,#852,.T.);
#874=ORIENTED_EDGE('',*,*,#668,.F.);
#875=EDGE_LOOP('',(#871,#872,#873,#874));
#876=FACE_BOUND('',#875,.T.);
#877=ADVANCED_FACE('F65',(#876),#870,.F.);
#878=CARTESIAN_POINT('',(0.,0.,11.1125000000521));
#879=DIRECTION('',(0.,0.,1.));
#880=DIRECTION('',(1.,0.,0.));
#881=AXIS2_PLACEMENT_3D('',#878,#879,#880);
#882=PLANE('',#881);
#883=CARTESIAN_POINT('',(0.,0.,11.1125000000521));
#884=DIRECTION('',(0.,0.,1.));
#885=DIRECTION('',(1.,0.,0.));
#886=AXIS2_PLACEMENT_3D('',#883,#884,#885);
#887=CIRCLE('',#886,46.101);
#888=CARTESIAN_POINT('',(46.101,0.,11.1125000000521));
#889=VERTEX_POINT('',#888);
#890=EDGE_CURVE('E344',#889,#889,#887,.T.);
#891=ORIENTED_EDGE('',*,*,#890,.T.);
#892=EDGE_LOOP('',(#891));
#893=FACE_BOUND('',#892,.T.);
#894=CARTESIAN_POINT('',(0.,0.,11.1125000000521));
#895=DIRECTION('',(0.,0.,1.));
#896=DIRECTION('',(1.,0.,0.));
#897=AXIS2_PLACEMENT_3D('',#894,#895,#896);
#898=CIRCLE('',#897,26.289);
#899=CARTESIAN_POINT('',(26.289,0.,11.1125000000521));
#900=VERTEX_POINT('',#899);
#901=EDGE_CURVE('E38',#900,#900,#898,.F.);
#902=ORIENTED_EDGE('',*,*,#901,.T.);
#903=EDGE_LOOP('',(#902));
#904=FACE_BOUND('',#903,.T.);
#905=ADVANCED_FACE('F294',(#893,#904),#882,.T.);
#906=CARTESIAN_POINT('',(0.,0.,11.1125000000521));
#907=DIRECTION('',(0.,0.,1.));
#908=DIRECTION('',(1.,0.,0.));
#909=AXIS2_PLACEMENT_3D('',#906,#907,#908);
#910=CYLINDRICAL_SURFACE('',#909,46.101);
#911=ORIENTED_EDGE('',*,*,#890,.F.);
#912=EDGE_LOOP('',(#911));
#913=FACE_BOUND('',#912,.T.);
#914=ORIENTED_EDGE('',*,*,#103,.T.);
#915=EDGE_LOOP('',(#914));
#916=FACE_BOUND('',#915,.T.);
#917=ADVANCED_FACE('F304',(#913,#916),#910,.F.);
#918=CARTESIAN_POINT('',(0.,0.,-114.3));
#919=DIRECTION('',(0.,0.,1.));
#920=DIRECTION('',(1.,0.,0.));
#921=AXIS2_PLACEMENT_3D('',#918,#919,#920);
#922=PLANE('',#921);
#923=CARTESIAN_POINT('',(0.,0.,-114.3));
#924=DIRECTION('',(0.,0.,1.));
#925=DIRECTION('',(1.,0.,0.));
#926=AXIS2_PLACEMENT_3D('',#923,#924,#925);
#927=CIRCLE('',#926,26.289);
#928=CARTESIAN_POINT('',(26.289,0.,-114.3));
#929=VERTEX_POINT('',#928);
#930=EDGE_CURVE('E70',#929,#929,#927,.T.);
#931=ORIENTED_EDGE('',*,*,#930,.T.);
#932=EDGE_LOOP('',(#931));
#933=FACE_BOUND('',#932,.T.);
#934=ADVANCED_FACE('F300',(#933),#922,.T.);
#935=CARTESIAN_POINT('',(0.,0.,-114.3));
#936=DIRECTION('',(0.,0.,1.));
#937=DIRECTION('',(1.,0.,0.));
#938=AXIS2_PLACEMENT_3D('',#935,#936,#937);
#939=CYLINDRICAL_SURFACE('',#938,26.289);
#940=ORIENTED_EDGE('',*,*,#930,.F.);
#941=EDGE_LOOP('',(#940));
#942=FACE_BOUND('',#941,.T.);
#943=ORIENTED_EDGE('',*,*,#901,.F.);
#944=EDGE_LOOP('',(#943));
#945=FACE_BOUND('',#944,.T.);
#946=ADVANCED_FACE('F303',(#942,#945),#939,.F.);
#947=CLOSED_SHELL('',(#90,#162,#174,#186,#198,#210,#222,#672,#698,#825,#834,#846,#865,#877,#905,
#917,#934,#946));
#948=MANIFOLD_SOLID_BREP('B2',#947);
#949=ADVANCED_BREP_SHAPE_REPRESENTATION('',(#18,#948),#14);
#950=SHAPE_DEFINITION_REPRESENTATION(#9,#949);
ENDSEC;
END-ISO-10303-21;
